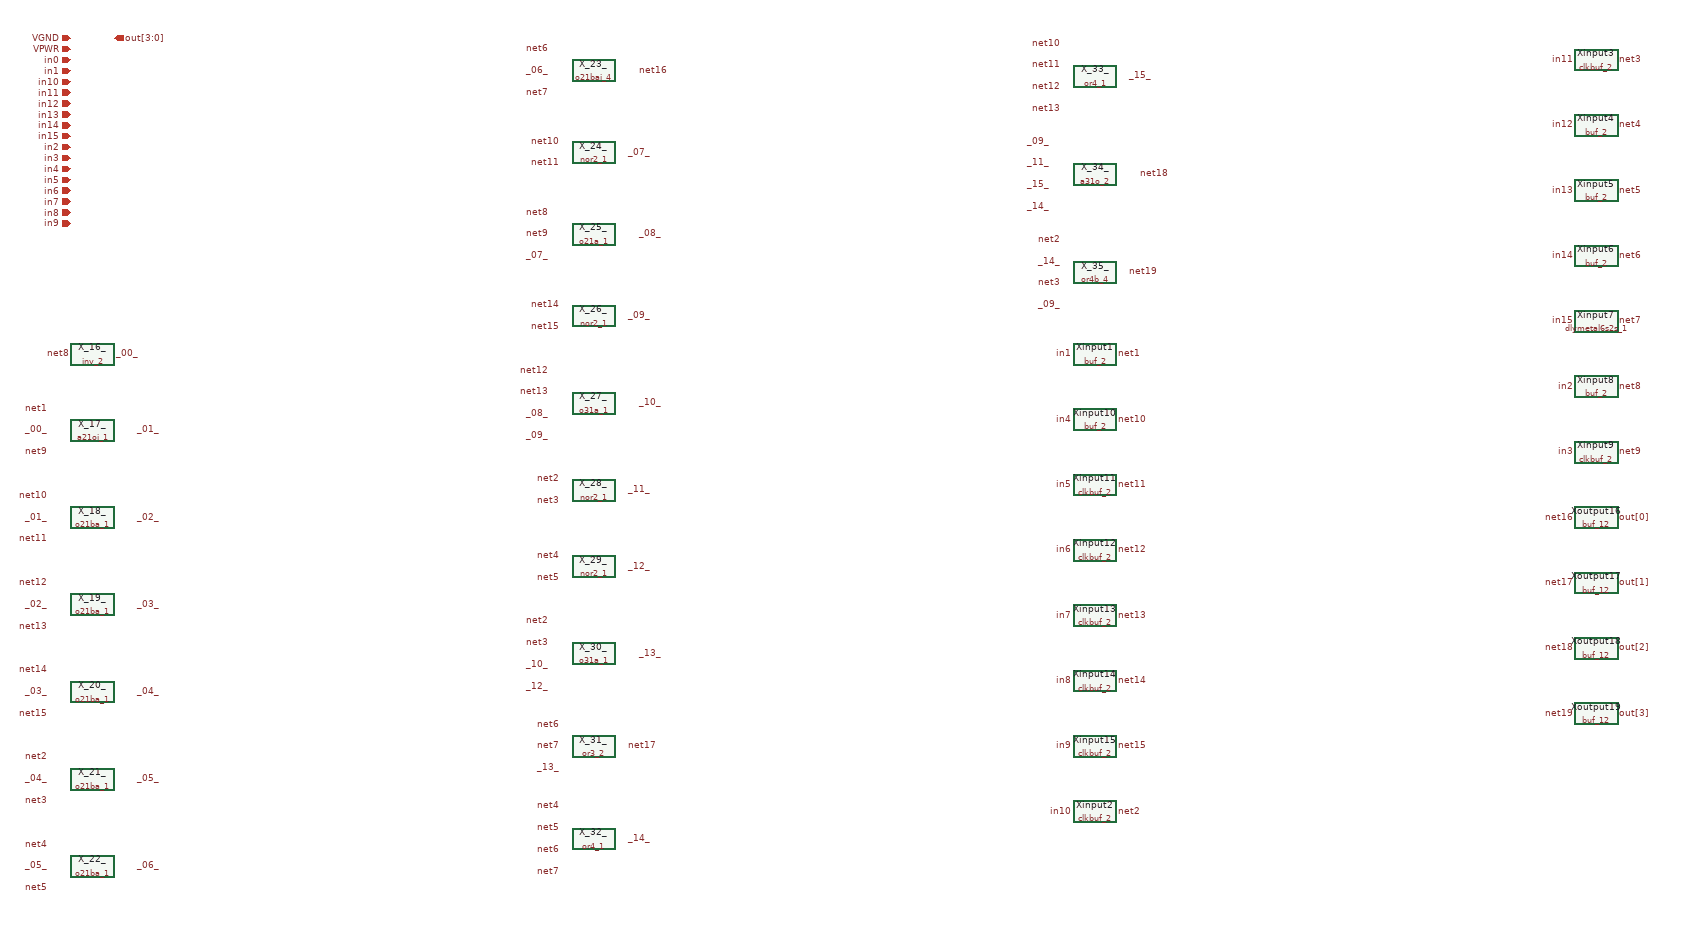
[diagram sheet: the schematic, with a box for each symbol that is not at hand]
v {xschem version=3.4.4 file_version=1.2
}
G {}
K {}
V {}
S {}
E {}
C {devices/ipin.sym} 190 20 0 0 {name=p162 lab=VGND }
C {devices/ipin.sym} 190 40 0 0 {name=p163 lab=VPWR }
C {devices/ipin.sym} 190 60 0 0 {name=p164 lab=in0 }
C {devices/ipin.sym} 190 80 0 0 {name=p165 lab=in1 }
C {devices/ipin.sym} 190 100 0 0 {name=p166 lab=in10 }
C {devices/ipin.sym} 190 120 0 0 {name=p167 lab=in11 }
C {devices/ipin.sym} 190 140 0 0 {name=p168 lab=in12 }
C {devices/ipin.sym} 190 160 0 0 {name=p169 lab=in13 }
C {devices/ipin.sym} 190 180 0 0 {name=p170 lab=in14 }
C {devices/ipin.sym} 190 200 0 0 {name=p171 lab=in15 }
C {devices/ipin.sym} 190 220 0 0 {name=p172 lab=in2 }
C {devices/ipin.sym} 190 240 0 0 {name=p173 lab=in3 }
C {devices/ipin.sym} 190 260 0 0 {name=p174 lab=in4 }
C {devices/ipin.sym} 190 280 0 0 {name=p175 lab=in5 }
C {devices/ipin.sym} 190 300 0 0 {name=p176 lab=in6 }
C {devices/ipin.sym} 190 320 0 0 {name=p177 lab=in7 }
C {devices/ipin.sym} 190 340 0 0 {name=p178 lab=in8 }
C {devices/ipin.sym} 190 360 0 0 {name=p179 lab=in9 }
C {devices/opin.sym} 270 20 0 0 {name=p180 lab=out[3:0] }
C {devices/lab_pin.sym} 190 600 0 0 {name=p44 lab=net8 }
C {devices/lab_pin.sym} 270 600 0 1 {name=p45 lab=_00_ }
C {sky130_stdcells/inv_2.sym} 230 600 0 0 {name=X_16_ VGND=VGND VNB=VGND VPB=VPWR VPWR=VPWR }
C {devices/lab_pin.sym} 150 700 0 0 {name=p46 lab=net1 }
C {devices/lab_pin.sym} 150 740 0 0 {name=p47 lab=_00_ }
C {devices/lab_pin.sym} 150 780 0 0 {name=p48 lab=net9 }
C {devices/lab_pin.sym} 310 740 0 1 {name=p49 lab=_01_ }
C {sky130_stdcells/a21oi_1.sym} 230 740 0 0 {name=X_17_ VGND=VGND VNB=VGND VPB=VPWR VPWR=VPWR }
C {devices/lab_pin.sym} 150 860 0 0 {name=p50 lab=net10 }
C {devices/lab_pin.sym} 150 900 0 0 {name=p51 lab=_01_ }
C {devices/lab_pin.sym} 150 940 0 0 {name=p52 lab=net11 }
C {devices/lab_pin.sym} 310 900 0 1 {name=p53 lab=_02_ }
C {sky130_stdcells/o21ba_1.sym} 230 900 0 0 {name=X_18_ VGND=VGND VNB=VGND VPB=VPWR VPWR=VPWR }
C {devices/lab_pin.sym} 150 1020 0 0 {name=p54 lab=net12 }
C {devices/lab_pin.sym} 150 1060 0 0 {name=p55 lab=_02_ }
C {devices/lab_pin.sym} 150 1100 0 0 {name=p56 lab=net13 }
C {devices/lab_pin.sym} 310 1060 0 1 {name=p57 lab=_03_ }
C {sky130_stdcells/o21ba_1.sym} 230 1060 0 0 {name=X_19_ VGND=VGND VNB=VGND VPB=VPWR VPWR=VPWR }
C {devices/lab_pin.sym} 150 1180 0 0 {name=p58 lab=net14 }
C {devices/lab_pin.sym} 150 1220 0 0 {name=p59 lab=_03_ }
C {devices/lab_pin.sym} 150 1260 0 0 {name=p60 lab=net15 }
C {devices/lab_pin.sym} 310 1220 0 1 {name=p61 lab=_04_ }
C {sky130_stdcells/o21ba_1.sym} 230 1220 0 0 {name=X_20_ VGND=VGND VNB=VGND VPB=VPWR VPWR=VPWR }
C {devices/lab_pin.sym} 150 1340 0 0 {name=p62 lab=net2 }
C {devices/lab_pin.sym} 150 1380 0 0 {name=p63 lab=_04_ }
C {devices/lab_pin.sym} 150 1420 0 0 {name=p64 lab=net3 }
C {devices/lab_pin.sym} 310 1380 0 1 {name=p65 lab=_05_ }
C {sky130_stdcells/o21ba_1.sym} 230 1380 0 0 {name=X_21_ VGND=VGND VNB=VGND VPB=VPWR VPWR=VPWR }
C {devices/lab_pin.sym} 150 1500 0 0 {name=p66 lab=net4 }
C {devices/lab_pin.sym} 150 1540 0 0 {name=p67 lab=_05_ }
C {devices/lab_pin.sym} 150 1580 0 0 {name=p68 lab=net5 }
C {devices/lab_pin.sym} 310 1540 0 1 {name=p69 lab=_06_ }
C {sky130_stdcells/o21ba_1.sym} 230 1540 0 0 {name=X_22_ VGND=VGND VNB=VGND VPB=VPWR VPWR=VPWR }
C {devices/lab_pin.sym} 1070 40 0 0 {name=p70 lab=net6 }
C {devices/lab_pin.sym} 1070 80 0 0 {name=p71 lab=_06_ }
C {devices/lab_pin.sym} 1070 120 0 0 {name=p72 lab=net7 }
C {devices/lab_pin.sym} 1230 80 0 1 {name=p73 lab=net16 }
C {sky130_stdcells/o21bai_4.sym} 1150 80 0 0 {name=X_23_ VGND=VGND VNB=VGND VPB=VPWR VPWR=VPWR }
C {devices/lab_pin.sym} 1090 210 0 0 {name=p74 lab=net10 }
C {devices/lab_pin.sym} 1090 250 0 0 {name=p75 lab=net11 }
C {devices/lab_pin.sym} 1210 230 0 1 {name=p76 lab=_07_ }
C {sky130_stdcells/nor2_1.sym} 1150 230 0 0 {name=X_24_ VGND=VGND VNB=VGND VPB=VPWR VPWR=VPWR }
C {devices/lab_pin.sym} 1070 340 0 0 {name=p77 lab=net8 }
C {devices/lab_pin.sym} 1070 380 0 0 {name=p78 lab=net9 }
C {devices/lab_pin.sym} 1070 420 0 0 {name=p79 lab=_07_ }
C {devices/lab_pin.sym} 1230 380 0 1 {name=p80 lab=_08_ }
C {sky130_stdcells/o21a_1.sym} 1150 380 0 0 {name=X_25_ VGND=VGND VNB=VGND VPB=VPWR VPWR=VPWR }
C {devices/lab_pin.sym} 1090 510 0 0 {name=p81 lab=net14 }
C {devices/lab_pin.sym} 1090 550 0 0 {name=p82 lab=net15 }
C {devices/lab_pin.sym} 1210 530 0 1 {name=p83 lab=_09_ }
C {sky130_stdcells/nor2_1.sym} 1150 530 0 0 {name=X_26_ VGND=VGND VNB=VGND VPB=VPWR VPWR=VPWR }
C {devices/lab_pin.sym} 1070 630 0 0 {name=p84 lab=net12 }
C {devices/lab_pin.sym} 1070 670 0 0 {name=p85 lab=net13 }
C {devices/lab_pin.sym} 1070 710 0 0 {name=p86 lab=_08_ }
C {devices/lab_pin.sym} 1070 750 0 0 {name=p87 lab=_09_ }
C {devices/lab_pin.sym} 1230 690 0 1 {name=p88 lab=_10_ }
C {sky130_stdcells/o31a_1.sym} 1150 690 0 0 {name=X_27_ VGND=VGND VNB=VGND VPB=VPWR VPWR=VPWR }
C {devices/lab_pin.sym} 1090 830 0 0 {name=p89 lab=net2 }
C {devices/lab_pin.sym} 1090 870 0 0 {name=p90 lab=net3 }
C {devices/lab_pin.sym} 1210 850 0 1 {name=p91 lab=_11_ }
C {sky130_stdcells/nor2_1.sym} 1150 850 0 0 {name=X_28_ VGND=VGND VNB=VGND VPB=VPWR VPWR=VPWR }
C {devices/lab_pin.sym} 1090 970 0 0 {name=p92 lab=net4 }
C {devices/lab_pin.sym} 1090 1010 0 0 {name=p93 lab=net5 }
C {devices/lab_pin.sym} 1210 990 0 1 {name=p94 lab=_12_ }
C {sky130_stdcells/nor2_1.sym} 1150 990 0 0 {name=X_29_ VGND=VGND VNB=VGND VPB=VPWR VPWR=VPWR }
C {devices/lab_pin.sym} 1070 1090 0 0 {name=p95 lab=net2 }
C {devices/lab_pin.sym} 1070 1130 0 0 {name=p96 lab=net3 }
C {devices/lab_pin.sym} 1070 1170 0 0 {name=p97 lab=_10_ }
C {devices/lab_pin.sym} 1070 1210 0 0 {name=p98 lab=_12_ }
C {devices/lab_pin.sym} 1230 1150 0 1 {name=p99 lab=_13_ }
C {sky130_stdcells/o31a_1.sym} 1150 1150 0 0 {name=X_30_ VGND=VGND VNB=VGND VPB=VPWR VPWR=VPWR }
C {devices/lab_pin.sym} 1090 1280 0 0 {name=p100 lab=net6 }
C {devices/lab_pin.sym} 1090 1320 0 0 {name=p101 lab=net7 }
C {devices/lab_pin.sym} 1090 1360 0 0 {name=p102 lab=_13_ }
C {devices/lab_pin.sym} 1210 1320 0 1 {name=p103 lab=net17 }
C {sky130_stdcells/or3_2.sym} 1150 1320 0 0 {name=X_31_ VGND=VGND VNB=VGND VPB=VPWR VPWR=VPWR }
C {devices/lab_pin.sym} 1090 1430 0 0 {name=p104 lab=net4 }
C {devices/lab_pin.sym} 1090 1470 0 0 {name=p105 lab=net5 }
C {devices/lab_pin.sym} 1090 1510 0 0 {name=p106 lab=net6 }
C {devices/lab_pin.sym} 1090 1550 0 0 {name=p107 lab=net7 }
C {devices/lab_pin.sym} 1210 1490 0 1 {name=p108 lab=_14_ }
C {sky130_stdcells/or4_1.sym} 1150 1490 0 0 {name=X_32_ VGND=VGND VNB=VGND VPB=VPWR VPWR=VPWR }
C {devices/lab_pin.sym} 2010 30 0 0 {name=p109 lab=net10 }
C {devices/lab_pin.sym} 2010 70 0 0 {name=p110 lab=net11 }
C {devices/lab_pin.sym} 2010 110 0 0 {name=p111 lab=net12 }
C {devices/lab_pin.sym} 2010 150 0 0 {name=p112 lab=net13 }
C {devices/lab_pin.sym} 2130 90 0 1 {name=p113 lab=_15_ }
C {sky130_stdcells/or4_1.sym} 2070 90 0 0 {name=X_33_ VGND=VGND VNB=VGND VPB=VPWR VPWR=VPWR }
C {devices/lab_pin.sym} 1990 210 0 0 {name=p114 lab=_09_ }
C {devices/lab_pin.sym} 1990 250 0 0 {name=p115 lab=_11_ }
C {devices/lab_pin.sym} 1990 290 0 0 {name=p116 lab=_15_ }
C {devices/lab_pin.sym} 1990 330 0 0 {name=p117 lab=_14_ }
C {devices/lab_pin.sym} 2150 270 0 1 {name=p118 lab=net18 }
C {sky130_stdcells/a31o_2.sym} 2070 270 0 0 {name=X_34_ VGND=VGND VNB=VGND VPB=VPWR VPWR=VPWR }
C {devices/lab_pin.sym} 2010 390 0 0 {name=p119 lab=net2 }
C {devices/lab_pin.sym} 2010 430 0 0 {name=p120 lab=_14_ }
C {devices/lab_pin.sym} 2010 470 0 0 {name=p121 lab=net3 }
C {devices/lab_pin.sym} 2010 510 0 0 {name=p122 lab=_09_ }
C {devices/lab_pin.sym} 2130 450 0 1 {name=p123 lab=net19 }
C {sky130_stdcells/or4b_4.sym} 2070 450 0 0 {name=X_35_ VGND=VGND VNB=VGND VPB=VPWR VPWR=VPWR }
C {devices/lab_pin.sym} 2030 600 0 0 {name=p124 lab=in1 }
C {devices/lab_pin.sym} 2110 600 0 1 {name=p125 lab=net1 }
C {sky130_stdcells/buf_2.sym} 2070 600 0 0 {name=Xinput1 VGND=VGND VNB=VGND VPB=VPWR VPWR=VPWR }
C {devices/lab_pin.sym} 2030 720 0 0 {name=p126 lab=in4 }
C {devices/lab_pin.sym} 2110 720 0 1 {name=p127 lab=net10 }
C {sky130_stdcells/buf_2.sym} 2070 720 0 0 {name=Xinput10 VGND=VGND VNB=VGND VPB=VPWR VPWR=VPWR }
C {devices/lab_pin.sym} 2030 840 0 0 {name=p128 lab=in5 }
C {devices/lab_pin.sym} 2110 840 0 1 {name=p129 lab=net11 }
C {sky130_stdcells/clkbuf_2.sym} 2070 840 0 0 {name=Xinput11 VGND=VGND VNB=VGND VPB=VPWR VPWR=VPWR }
C {devices/lab_pin.sym} 2030 960 0 0 {name=p130 lab=in6 }
C {devices/lab_pin.sym} 2110 960 0 1 {name=p131 lab=net12 }
C {sky130_stdcells/clkbuf_2.sym} 2070 960 0 0 {name=Xinput12 VGND=VGND VNB=VGND VPB=VPWR VPWR=VPWR }
C {devices/lab_pin.sym} 2030 1080 0 0 {name=p132 lab=in7 }
C {devices/lab_pin.sym} 2110 1080 0 1 {name=p133 lab=net13 }
C {sky130_stdcells/clkbuf_2.sym} 2070 1080 0 0 {name=Xinput13 VGND=VGND VNB=VGND VPB=VPWR VPWR=VPWR }
C {devices/lab_pin.sym} 2030 1200 0 0 {name=p134 lab=in8 }
C {devices/lab_pin.sym} 2110 1200 0 1 {name=p135 lab=net14 }
C {sky130_stdcells/clkbuf_2.sym} 2070 1200 0 0 {name=Xinput14 VGND=VGND VNB=VGND VPB=VPWR VPWR=VPWR }
C {devices/lab_pin.sym} 2030 1320 0 0 {name=p136 lab=in9 }
C {devices/lab_pin.sym} 2110 1320 0 1 {name=p137 lab=net15 }
C {sky130_stdcells/clkbuf_2.sym} 2070 1320 0 0 {name=Xinput15 VGND=VGND VNB=VGND VPB=VPWR VPWR=VPWR }
C {devices/lab_pin.sym} 2030 1440 0 0 {name=p138 lab=in10 }
C {devices/lab_pin.sym} 2110 1440 0 1 {name=p139 lab=net2 }
C {sky130_stdcells/clkbuf_2.sym} 2070 1440 0 0 {name=Xinput2 VGND=VGND VNB=VGND VPB=VPWR VPWR=VPWR }
C {devices/lab_pin.sym} 2950 60 0 0 {name=p140 lab=in11 }
C {devices/lab_pin.sym} 3030 60 0 1 {name=p141 lab=net3 }
C {sky130_stdcells/clkbuf_2.sym} 2990 60 0 0 {name=Xinput3 VGND=VGND VNB=VGND VPB=VPWR VPWR=VPWR }
C {devices/lab_pin.sym} 2950 180 0 0 {name=p142 lab=in12 }
C {devices/lab_pin.sym} 3030 180 0 1 {name=p143 lab=net4 }
C {sky130_stdcells/buf_2.sym} 2990 180 0 0 {name=Xinput4 VGND=VGND VNB=VGND VPB=VPWR VPWR=VPWR }
C {devices/lab_pin.sym} 2950 300 0 0 {name=p144 lab=in13 }
C {devices/lab_pin.sym} 3030 300 0 1 {name=p145 lab=net5 }
C {sky130_stdcells/buf_2.sym} 2990 300 0 0 {name=Xinput5 VGND=VGND VNB=VGND VPB=VPWR VPWR=VPWR }
C {devices/lab_pin.sym} 2950 420 0 0 {name=p146 lab=in14 }
C {devices/lab_pin.sym} 3030 420 0 1 {name=p147 lab=net6 }
C {sky130_stdcells/buf_2.sym} 2990 420 0 0 {name=Xinput6 VGND=VGND VNB=VGND VPB=VPWR VPWR=VPWR }
C {devices/lab_pin.sym} 2950 540 0 0 {name=p148 lab=in15 }
C {devices/lab_pin.sym} 3030 540 0 1 {name=p149 lab=net7 }
C {sky130_stdcells/dlymetal6s2s_1.sym} 2990 540 0 0 {name=Xinput7 VGND=VGND VNB=VGND VPB=VPWR VPWR=VPWR }
C {devices/lab_pin.sym} 2950 660 0 0 {name=p150 lab=in2 }
C {devices/lab_pin.sym} 3030 660 0 1 {name=p151 lab=net8 }
C {sky130_stdcells/buf_2.sym} 2990 660 0 0 {name=Xinput8 VGND=VGND VNB=VGND VPB=VPWR VPWR=VPWR }
C {devices/lab_pin.sym} 2950 780 0 0 {name=p152 lab=in3 }
C {devices/lab_pin.sym} 3030 780 0 1 {name=p153 lab=net9 }
C {sky130_stdcells/clkbuf_2.sym} 2990 780 0 0 {name=Xinput9 VGND=VGND VNB=VGND VPB=VPWR VPWR=VPWR }
C {devices/lab_pin.sym} 2950 900 0 0 {name=p154 lab=net16 }
C {devices/lab_pin.sym} 3030 900 0 1 {name=p155 lab=out[0] }
C {sky130_stdcells/buf_12.sym} 2990 900 0 0 {name=Xoutput16 VGND=VGND VNB=VGND VPB=VPWR VPWR=VPWR }
C {devices/lab_pin.sym} 2950 1020 0 0 {name=p156 lab=net17 }
C {devices/lab_pin.sym} 3030 1020 0 1 {name=p157 lab=out[1] }
C {sky130_stdcells/buf_12.sym} 2990 1020 0 0 {name=Xoutput17 VGND=VGND VNB=VGND VPB=VPWR VPWR=VPWR }
C {devices/lab_pin.sym} 2950 1140 0 0 {name=p158 lab=net18 }
C {devices/lab_pin.sym} 3030 1140 0 1 {name=p159 lab=out[2] }
C {sky130_stdcells/buf_12.sym} 2990 1140 0 0 {name=Xoutput18 VGND=VGND VNB=VGND VPB=VPWR VPWR=VPWR }
C {devices/lab_pin.sym} 2950 1260 0 0 {name=p160 lab=net19 }
C {devices/lab_pin.sym} 3030 1260 0 1 {name=p161 lab=out[3] }
C {sky130_stdcells/buf_12.sym} 2990 1260 0 0 {name=Xoutput19 VGND=VGND VNB=VGND VPB=VPWR VPWR=VPWR }
